VERSION 5.7 ;
DIVIDERCHAR "/" ;
BUSBITCHARS "[]" ;

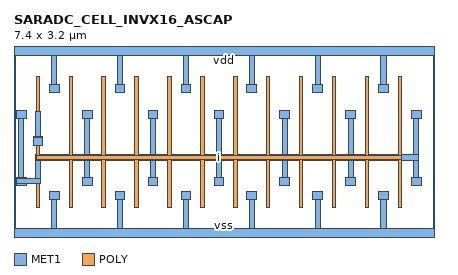
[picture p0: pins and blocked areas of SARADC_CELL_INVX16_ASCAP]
MACRO SARADC_CELL_INVX16_ASCAP
  CLASS BLOCK ;
  FOREIGN SARADC_CELL_INVX16_ASCAP ;
  ORIGIN 0.000 0.000 ;
  SIZE 7.400 BY 3.200 ;
  SYMMETRY X Y R90 ;
  PIN vnw
  END vnw
  PIN vpw
  END vpw
  PIN vdd
    DIRECTION INOUT ;
    USE POWER ;
    PORT
      LAYER MET1 ;
        RECT 0.625 2.470 0.795 2.610 ;
        RECT 1.785 2.470 1.955 2.610 ;
        RECT 2.945 2.470 3.115 2.610 ;
        RECT 4.105 2.470 4.275 2.610 ;
        RECT 5.265 2.470 5.435 2.610 ;
        RECT 6.425 2.470 6.595 2.610 ;
        RECT 0.665 2.610 0.755 3.120 ;
        RECT 1.825 2.610 1.915 3.120 ;
        RECT 2.985 2.610 3.075 3.120 ;
        RECT 4.145 2.610 4.235 3.120 ;
        RECT 5.305 2.610 5.395 3.120 ;
        RECT 6.465 2.610 6.555 3.120 ;
        RECT 0.000 3.120 7.400 3.280 ;
    END
  END vdd
  PIN vss
    DIRECTION INOUT ;
    USE GROUND ;
    PORT
      LAYER MET1 ;
        RECT 0.000 -0.080 7.400 0.080 ;
        RECT 0.665 0.080 0.755 0.590 ;
        RECT 1.825 0.080 1.915 0.590 ;
        RECT 2.985 0.080 3.075 0.590 ;
        RECT 4.145 0.080 4.235 0.590 ;
        RECT 5.305 0.080 5.395 0.590 ;
        RECT 6.465 0.080 6.555 0.590 ;
        RECT 0.625 0.590 0.795 0.730 ;
        RECT 1.785 0.590 1.955 0.730 ;
        RECT 2.945 0.590 3.115 0.730 ;
        RECT 4.105 0.590 4.275 0.730 ;
        RECT 5.265 0.590 5.435 0.730 ;
        RECT 6.425 0.590 6.595 0.730 ;
    END
  END vss
  PIN i
    DIRECTION INOUT ;
    USE POWER ;
    PORT
      LAYER POLY ;
        RECT 0.390 0.445 0.450 1.300 ;
        RECT 0.970 0.445 1.030 1.300 ;
        RECT 1.550 0.445 1.610 1.300 ;
        RECT 2.130 0.445 2.190 1.300 ;
        RECT 2.710 0.445 2.770 1.300 ;
        RECT 3.290 0.445 3.350 1.300 ;
        RECT 3.870 0.445 3.930 1.300 ;
        RECT 4.450 0.445 4.510 1.300 ;
        RECT 5.030 0.445 5.090 1.300 ;
        RECT 5.610 0.445 5.670 1.300 ;
        RECT 6.190 0.445 6.250 1.300 ;
        RECT 6.770 0.445 6.830 1.300 ;
        RECT 0.390 1.300 6.830 1.360 ;
        RECT 0.390 1.360 0.450 1.535 ;
        RECT 0.970 1.360 1.030 2.755 ;
        RECT 1.550 1.360 1.610 2.755 ;
        RECT 2.130 1.360 2.190 2.755 ;
        RECT 2.710 1.360 2.770 2.755 ;
        RECT 3.290 1.360 3.350 2.755 ;
        RECT 3.870 1.360 3.930 2.755 ;
        RECT 4.450 1.360 4.510 2.755 ;
        RECT 5.030 1.360 5.090 2.755 ;
        RECT 5.610 1.360 5.670 2.755 ;
        RECT 6.190 1.360 6.250 2.755 ;
        RECT 6.770 1.360 6.830 2.755 ;
        RECT 0.335 1.535 0.505 1.705 ;
        RECT 0.390 1.705 0.450 2.755 ;
      LAYER MET1 ;
        RECT 0.335 1.550 0.505 1.690 ;
        RECT 0.375 1.690 0.465 2.135 ;
    END
  END i
  PIN zn
    DIRECTION INOUT ;
    USE POWER ;
    PORT
      LAYER MET1 ;
        RECT 0.045 0.840 0.215 0.865 ;
        RECT 1.205 0.840 1.375 0.980 ;
        RECT 2.365 0.840 2.535 0.980 ;
        RECT 3.525 0.840 3.695 0.980 ;
        RECT 4.685 0.840 4.855 0.980 ;
        RECT 5.845 0.840 6.015 0.980 ;
        RECT 7.005 0.840 7.175 0.980 ;
        RECT 0.045 0.865 0.465 0.955 ;
        RECT 0.045 0.955 0.215 0.980 ;
        RECT 0.375 0.955 0.465 1.285 ;
        RECT 0.085 0.980 0.175 2.020 ;
        RECT 1.245 0.980 1.335 1.285 ;
        RECT 2.405 0.980 2.495 1.285 ;
        RECT 3.565 0.980 3.655 1.285 ;
        RECT 4.725 0.980 4.815 1.285 ;
        RECT 5.885 0.980 5.975 1.285 ;
        RECT 7.045 0.980 7.135 1.285 ;
        RECT 0.375 1.285 7.135 1.375 ;
        RECT 1.245 1.375 1.335 2.020 ;
        RECT 2.405 1.375 2.495 2.020 ;
        RECT 3.565 1.375 3.655 2.020 ;
        RECT 4.725 1.375 4.815 2.020 ;
        RECT 5.885 1.375 5.975 2.020 ;
        RECT 7.045 1.375 7.135 2.020 ;
        RECT 0.045 2.020 0.215 2.160 ;
        RECT 1.205 2.020 1.375 2.160 ;
        RECT 2.365 2.020 2.535 2.160 ;
        RECT 3.525 2.020 3.695 2.160 ;
        RECT 4.685 2.020 4.855 2.160 ;
        RECT 5.845 2.020 6.015 2.160 ;
        RECT 7.005 2.020 7.175 2.160 ;
    END
  END zn
END SARADC_CELL_INVX16_ASCAP

END LIBRARY
